VERSION 5.7 ;
  NOWIREEXTENSIONATPIN ON ;
  DIVIDERCHAR "/" ;
  BUSBITCHARS "[]" ;
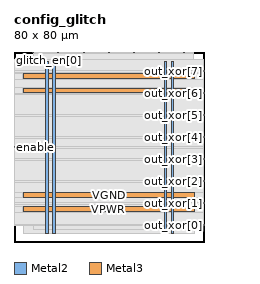
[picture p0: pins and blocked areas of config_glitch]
MACRO config_glitch
  CLASS BLOCK ;
  FOREIGN config_glitch ;
  ORIGIN 0.000 0.000 ;
  SIZE 80.000 BY 80.000 ;
  PIN VGND
    DIRECTION INOUT ;
    USE GROUND ;
    PORT
      LAYER Metal2 ;
        RECT 16.340 3.560 17.340 75.820 ;
    END
    PORT
      LAYER Metal2 ;
        RECT 66.340 3.560 67.340 75.820 ;
    END
    PORT
      LAYER Metal3 ;
        RECT 3.840 18.780 75.840 20.780 ;
    END
    PORT
      LAYER Metal3 ;
        RECT 3.840 68.780 75.840 70.780 ;
    END
  END VGND
  PIN VPWR
    DIRECTION INOUT ;
    USE POWER ;
    PORT
      LAYER Metal2 ;
        RECT 13.340 3.560 14.340 75.820 ;
    END
    PORT
      LAYER Metal2 ;
        RECT 63.340 3.560 64.340 75.820 ;
    END
    PORT
      LAYER Metal3 ;
        RECT 3.840 12.780 75.840 14.780 ;
    END
    PORT
      LAYER Metal3 ;
        RECT 3.840 62.780 75.840 64.780 ;
    END
  END VPWR
  PIN enable
    DIRECTION INPUT ;
    USE SIGNAL ;
    ANTENNAGATEAREA 1.450800 ;
    PORT
      LAYER Metal3 ;
        RECT 0.000 39.700 0.400 40.100 ;
    END
  END enable
  PIN glitch_en[0]
    DIRECTION INPUT ;
    USE SIGNAL ;
    ANTENNAGATEAREA 0.180700 ;
    PORT
      LAYER Metal2 ;
        RECT 7.960 79.600 8.360 80.000 ;
    END
  END glitch_en[0]
  PIN glitch_en[1]
    DIRECTION INPUT ;
    USE SIGNAL ;
    ANTENNAGATEAREA 0.180700 ;
    PORT
      LAYER Metal2 ;
        RECT 18.520 79.600 18.920 80.000 ;
    END
  END glitch_en[1]
  PIN glitch_en[2]
    DIRECTION INPUT ;
    USE SIGNAL ;
    ANTENNAGATEAREA 0.180700 ;
    PORT
      LAYER Metal2 ;
        RECT 29.080 79.600 29.480 80.000 ;
    END
  END glitch_en[2]
  PIN glitch_en[3]
    DIRECTION INPUT ;
    USE SIGNAL ;
    ANTENNAGATEAREA 0.180700 ;
    PORT
      LAYER Metal2 ;
        RECT 39.640 79.600 40.040 80.000 ;
    END
  END glitch_en[3]
  PIN glitch_en[4]
    DIRECTION INPUT ;
    USE SIGNAL ;
    ANTENNAGATEAREA 0.180700 ;
    PORT
      LAYER Metal2 ;
        RECT 50.200 79.600 50.600 80.000 ;
    END
  END glitch_en[4]
  PIN glitch_en[5]
    DIRECTION INPUT ;
    USE SIGNAL ;
    ANTENNAGATEAREA 0.180700 ;
    PORT
      LAYER Metal2 ;
        RECT 60.760 79.600 61.160 80.000 ;
    END
  END glitch_en[5]
  PIN glitch_en[6]
    DIRECTION INPUT ;
    USE SIGNAL ;
    ANTENNAGATEAREA 0.180700 ;
    PORT
      LAYER Metal2 ;
        RECT 71.320 79.600 71.720 80.000 ;
    END
  END glitch_en[6]
  PIN out_xor[0]
    DIRECTION OUTPUT ;
    USE SIGNAL ;
    ANTENNADIFFAREA 0.708600 ;
    PORT
      LAYER Metal3 ;
        RECT 79.600 6.940 80.000 7.340 ;
    END
  END out_xor[0]
  PIN out_xor[1]
    DIRECTION OUTPUT ;
    USE SIGNAL ;
    ANTENNADIFFAREA 0.708600 ;
    PORT
      LAYER Metal3 ;
        RECT 79.600 16.180 80.000 16.580 ;
    END
  END out_xor[1]
  PIN out_xor[2]
    DIRECTION OUTPUT ;
    USE SIGNAL ;
    ANTENNADIFFAREA 0.708600 ;
    PORT
      LAYER Metal3 ;
        RECT 79.600 25.420 80.000 25.820 ;
    END
  END out_xor[2]
  PIN out_xor[3]
    DIRECTION OUTPUT ;
    USE SIGNAL ;
    ANTENNADIFFAREA 0.708600 ;
    PORT
      LAYER Metal3 ;
        RECT 79.600 34.660 80.000 35.060 ;
    END
  END out_xor[3]
  PIN out_xor[4]
    DIRECTION OUTPUT ;
    USE SIGNAL ;
    ANTENNADIFFAREA 0.708600 ;
    PORT
      LAYER Metal3 ;
        RECT 79.600 43.900 80.000 44.300 ;
    END
  END out_xor[4]
  PIN out_xor[5]
    DIRECTION OUTPUT ;
    USE SIGNAL ;
    ANTENNADIFFAREA 0.708600 ;
    PORT
      LAYER Metal3 ;
        RECT 79.600 53.140 80.000 53.540 ;
    END
  END out_xor[5]
  PIN out_xor[6]
    DIRECTION OUTPUT ;
    USE SIGNAL ;
    ANTENNADIFFAREA 0.708600 ;
    PORT
      LAYER Metal3 ;
        RECT 79.600 62.380 80.000 62.780 ;
    END
  END out_xor[6]
  PIN out_xor[7]
    DIRECTION OUTPUT ;
    USE SIGNAL ;
    ANTENNADIFFAREA 0.708600 ;
    PORT
      LAYER Metal3 ;
        RECT 79.600 71.620 80.000 72.020 ;
    END
  END out_xor[7]
  OBS
      LAYER GatPoly ;
        RECT 3.840 3.630 75.840 75.750 ;
      LAYER Metal1 ;
        RECT 3.840 3.560 75.840 75.820 ;
      LAYER Metal2 ;
        RECT 8.570 79.390 18.310 79.600 ;
        RECT 19.130 79.390 28.870 79.600 ;
        RECT 29.690 79.390 39.430 79.600 ;
        RECT 40.250 79.390 49.990 79.600 ;
        RECT 50.810 79.390 60.550 79.600 ;
        RECT 61.370 79.390 71.110 79.600 ;
        RECT 71.930 79.390 75.465 79.600 ;
        RECT 8.060 76.030 75.465 79.390 ;
        RECT 8.060 5.315 13.130 76.030 ;
        RECT 14.550 5.315 16.130 76.030 ;
        RECT 17.550 5.315 63.130 76.030 ;
        RECT 64.550 5.315 66.130 76.030 ;
        RECT 67.550 5.315 75.465 76.030 ;
      LAYER Metal3 ;
        RECT 0.400 72.230 79.600 76.960 ;
        RECT 0.400 71.410 79.390 72.230 ;
        RECT 0.400 70.990 79.600 71.410 ;
        RECT 0.400 68.570 3.630 70.990 ;
        RECT 76.050 68.570 79.600 70.990 ;
        RECT 0.400 64.990 79.600 68.570 ;
        RECT 0.400 62.570 3.630 64.990 ;
        RECT 76.050 62.990 79.600 64.990 ;
        RECT 76.050 62.570 79.390 62.990 ;
        RECT 0.400 62.170 79.390 62.570 ;
        RECT 0.400 53.750 79.600 62.170 ;
        RECT 0.400 52.930 79.390 53.750 ;
        RECT 0.400 44.510 79.600 52.930 ;
        RECT 0.400 43.690 79.390 44.510 ;
        RECT 0.400 40.310 79.600 43.690 ;
        RECT 0.610 39.490 79.600 40.310 ;
        RECT 0.400 35.270 79.600 39.490 ;
        RECT 0.400 34.450 79.390 35.270 ;
        RECT 0.400 26.030 79.600 34.450 ;
        RECT 0.400 25.210 79.390 26.030 ;
        RECT 0.400 20.990 79.600 25.210 ;
        RECT 0.400 18.570 3.630 20.990 ;
        RECT 76.050 18.570 79.600 20.990 ;
        RECT 0.400 16.790 79.600 18.570 ;
        RECT 0.400 15.970 79.390 16.790 ;
        RECT 0.400 14.990 79.600 15.970 ;
        RECT 0.400 12.570 3.630 14.990 ;
        RECT 76.050 12.570 79.600 14.990 ;
        RECT 0.400 7.550 79.600 12.570 ;
        RECT 0.400 7.040 79.390 7.550 ;
  END
END config_glitch
END LIBRARY

